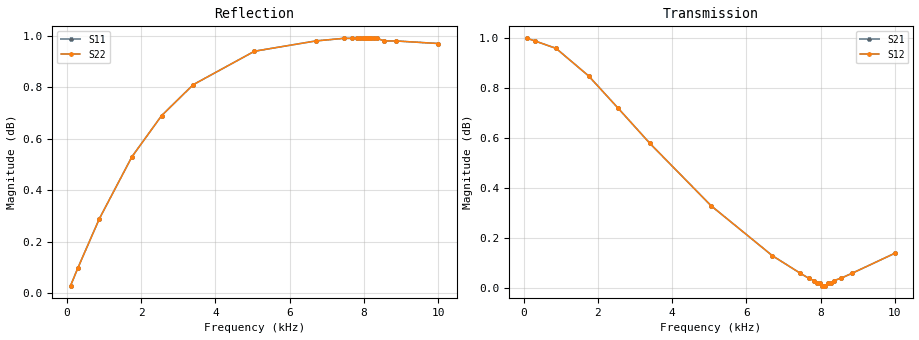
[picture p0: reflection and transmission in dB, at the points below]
! AVX Corporation
! PN: AS0605N5*TR
! DESCRIPTION: SQUARE AIR CORE INDUCTOR, 5.5nH, 3 turns
# Hz S dB R 50
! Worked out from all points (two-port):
!   397 points, 100 Hz to 10 kHz, reference 50 ohm
!   highest |S21| = 1.00 dB at 100 Hz (marker M1); lowest = 0.0 dB at 8.075 kHz (marker M2)
!   |S21| within 3 dB of the highest: start of sweep to end of sweep
!   lowest |S11| = 0.0 dB at 100 Hz (marker M3)
!   |S11| at or under -10 dB: nowhere
!   |S22| runs from 0.0 to 1.0 dB; largest |S21 - S12| = 0
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100  0.03 84.1  1.00 -2.0  1.00 -2.0  0.03 84.1
300  0.10 82.7  0.99 -6.0  0.99 -6.0  0.10 82.7
875  0.29 72.2  0.96 -17.4  0.96 -17.4  0.29 72.2
1750  0.53 56.5  0.85 -33.3  0.85 -33.3  0.53 56.5
2550  0.69 43.9  0.72 -45.9  0.72 -45.9  0.69 43.9
3400  0.81 32.4  0.58 -57.2  0.58 -57.2  0.81 32.4
5050  0.94 14.9  0.33 -74.1  0.33 -74.1  0.94 14.9
6700  0.98 1.7  0.13 -84.2  0.13 -84.2  0.98 1.7
7450  0.99 -3.3  0.06 -82.1  0.06 -82.1  0.99 -3.3
7675  0.99 -4.8  0.04 -76.5  0.04 -76.5  0.99 -4.8
7825  0.99 -5.7  0.03 -67.1  0.03 -67.1  0.99 -5.7
7900  0.99 -6.2  0.02 -58.2  0.02 -58.2  0.99 -6.2
7975  0.99 -6.6  0.02 -43.5  0.02 -43.5  0.99 -6.6
8025  0.99 -6.9  0.01 -29.2  0.01 -29.2  0.99 -6.9
8075  0.99 -7.2  0.01 -11.8  0.01 -11.8  0.99 -7.2
8125  0.99 -7.5  0.01 6.0  0.01 6.0  0.99 -7.5
8200  0.99 -7.9  0.02 27.2  0.02 27.2  0.99 -7.9
8275  0.99 -8.4  0.02 40.5  0.02 40.5  0.99 -8.4
8350  0.99 -8.8  0.03 48.7  0.03 48.7  0.99 -8.8
8550  0.98 -10.0  0.04 59.1  0.04 59.1  0.98 -10.0
8850  0.98 -11.6  0.06 64.2  0.06 64.2  0.98 -11.6
10000  0.97 -17.5  0.14 64.8  0.14 64.8  0.97 -17.5
